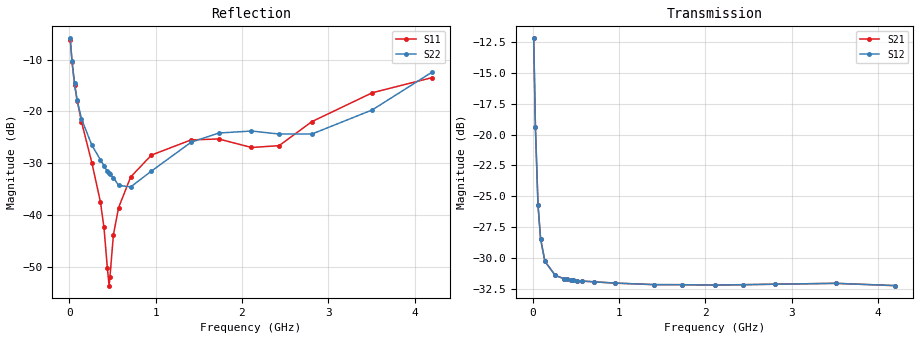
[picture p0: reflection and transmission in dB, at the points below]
! Integrated Device Technology
! Corporate Headquarters
! 6024 Silver Creek Valley Road
! San Jose, CA 95138  USA
! Phone:  1-408-284-8200
! Toll Free:  1-800-223-1366
! Webpage:  http://www.idt.com/
! Timing and RF Division
! 515 Groton Road, Suite 102
! Westford, MA 01886-6024
! Device:  F1950
! Description: 7-bit 0.25 dB Digital Step Attenuator
! Frequency:  150.0 -  4000.00 MHz
! Package:  4x4 mm Thin QFN Plastic Package: 24 pin
! Ports:  2 RF, 12 DC
!  Pin  1  = D0
!  Pin  2  = VDD
!  Pin  3  = Vmode
!  Pin  4  = GND
!  Pin  5  = RF1  =  Port 1
!  Pin  6  = GND
!  Pin  7  = GND
!  Pin  8  = GND
!  Pin  9  = GND
!  Pin 10  = GND
!  Pin 11  = GND
!  Pin 12  = GND
!  Pin 13  = GND
!  Pin 14  = RF2  =  Port 2
!  Pin 15  = GND
!  Pin 16  = LE
!  Pin 17  = CLK
!  Pin 18  = DATE
!  Pin 19  = D6
!  Pin 20  = D5
!  Pin 21  = D4
!  Pin 22  = D3
!  Pin 23  = D2
!  Pin 24  = D1
! State:  124
! Atten State:  31.00 dB
! Voltage:  +5.00 Volts
! Current:  Not Measured mA
! Data:  The device was measured on a the F195X evaluation board which has
!  individual transmission lines to the RF pins.  Data was collected
!  using a calibrated network analyzer.  The evaluation board was
!  de-embedded using a TRL calibration technique.
!  The reference plane is the edge of the package pin.
! Misc:  Board 2019
!  Action Tracker AT0250
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# GHz S dB R 50
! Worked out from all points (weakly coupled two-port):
!   420 points, 10 MHz to 4.2 GHz, reference 50 ohm
!   highest |S21| = -12.24 dB at 10 MHz (marker M1); lowest = -32.2 dB at 4.2 GHz (marker M2)
!   lowest |S11| = -53.6 dB at 460 MHz (marker M3), VSWR 1.00, Z = 49.8 - j0.0689 ohm
!   |S11| at or under -10 dB: 27.77 MHz to end of sweep
!   |S22| runs from -34.8 to -5.9 dB; largest |S21 - S12| = 6.4e-05
!   S11 on the Smith chart (normalised r, x): 10 MHz: 2.00, -1.24; 30 MHz: 1.27, -0.66; 60 MHz: 1.10, -0.37; 360 MHz: 1.01, -0.03; 4.2 GHz: 0.69, +0.17
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0.01  -6.20 -28.6  -12.24 -42.1  -12.24 -42.1  -5.93 -29.3
0.03  -10.44 -51.7  -19.42 -66.4  -19.42 -66.4  -10.23 -53.7
0.06  -14.92 -64.3  -25.68 -61.2  -25.68 -61.2  -14.62 -66.3
0.09  -17.96 -70.0  -28.42 -50.0  -28.42 -50.0  -17.85 -70.7
0.14  -21.99 -72.8  -30.24 -36.7  -30.24 -36.7  -21.46 -75.2
0.26  -29.87 -71.9  -31.37 -22.7  -31.37 -22.6  -26.49 -81.0
0.36  -37.47 -72.1  -31.63 -17.9  -31.63 -17.9  -29.33 -87.3
0.4  -42.26 -78.2  -31.68 -16.7  -31.69 -16.8  -30.43 -89.1
0.44  -50.16 -106.9  -31.73 -15.9  -31.73 -15.9  -31.55 -93.8
0.46  -53.55 -160.8  -31.75 -15.5  -31.75 -15.5  -31.94 -97.2
0.47  -51.82 171.0  -31.76 -15.3  -31.76 -15.3  -32.09 -98.9
0.51  -43.74 143.4  -31.79 -14.7  -31.79 -14.7  -32.77 -103.0
0.57  -38.52 136.4  -31.83 -14.1  -31.82 -14.1  -34.22 -113.9
0.71  -32.62 138.3  -31.89 -13.2  -31.89 -13.2  -34.54 -141.4
0.95  -28.41 146.2  -31.99 -13.0  -31.99 -13.0  -31.49 -177.3
1.41  -25.48 162.3  -32.12 -13.9  -32.11 -13.9  -25.93 160.2
1.73  -25.30 167.3  -32.12 -14.8  -32.12 -14.8  -24.16 151.8
2.11  -26.94 156.6  -32.15 -16.9  -32.15 -17.0  -23.77 141.8
2.43  -26.59 125.3  -32.12 -18.0  -32.12 -18.0  -24.35 131.0
2.81  -21.96 104.9  -32.08 -20.3  -32.08 -20.4  -24.35 115.7
3.51  -16.40 117.0  -32.01 -24.2  -32.01 -24.2  -19.70 113.1
4.2  -13.50 145.2  -32.20 -25.2  -32.19 -25.3  -12.46 127.0
